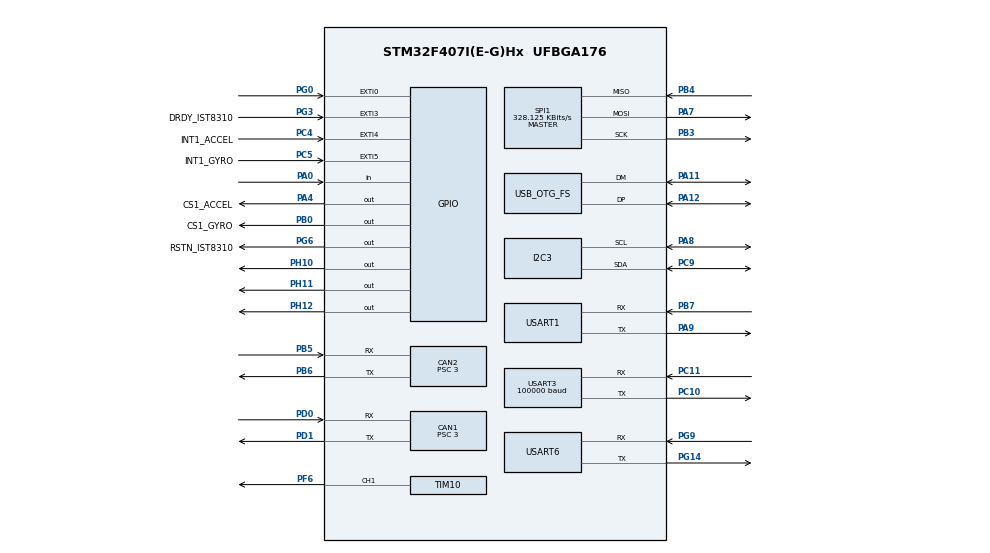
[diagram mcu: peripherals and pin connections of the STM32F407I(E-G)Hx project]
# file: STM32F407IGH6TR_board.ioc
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CAN1.ABOM=ENABLE
CAN1.BS1=CAN_BS1_9TQ
CAN1.BS2=CAN_BS2_4TQ
CAN1.CalculateBaudRate=1000000
CAN1.CalculateTimeBit=1000
CAN1.CalculateTimeQuantum=71.42857142857143
CAN1.Prescaler=3
CAN2.ABOM=ENABLE
CAN2.BS1=CAN_BS1_9TQ
CAN2.BS2=CAN_BS2_4TQ
CAN2.CalculateBaudRate=1000000
CAN2.CalculateTimeBit=1000
CAN2.CalculateTimeQuantum=71.42857142857143
CAN2.Prescaler=3
Dma.Request0=USART6_RX
Dma.Request1=USART6_TX
Dma.Request2=USART3_RX
Dma.Request3=USART1_RX
Dma.Request4=USART1_TX
Dma.Request5=SPI1_RX
Dma.Request6=SPI1_TX
Dma.SPI1_RX.5.Direction=DMA_PERIPH_TO_MEMORY
Dma.SPI1_RX.5.FIFOMode=DMA_FIFOMODE_DISABLE
Dma.SPI1_RX.5.Instance=DMA2_Stream2
Dma.SPI1_RX.5.MemDataAlignment=DMA_MDATAALIGN_BYTE
Dma.SPI1_RX.5.MemInc=DMA_MINC_ENABLE
Dma.SPI1_RX.5.Mode=DMA_NORMAL
Dma.SPI1_RX.5.PeriphDataAlignment=DMA_PDATAALIGN_BYTE
Dma.SPI1_RX.5.PeriphInc=DMA_PINC_DISABLE
Dma.SPI1_RX.5.Priority=DMA_PRIORITY_VERY_HIGH
Dma.SPI1_TX.6.Direction=DMA_MEMORY_TO_PERIPH
Dma.SPI1_TX.6.FIFOMode=DMA_FIFOMODE_DISABLE
Dma.SPI1_TX.6.Instance=DMA2_Stream3
Dma.SPI1_TX.6.MemDataAlignment=DMA_MDATAALIGN_BYTE
Dma.SPI1_TX.6.MemInc=DMA_MINC_ENABLE
Dma.SPI1_TX.6.Mode=DMA_NORMAL
Dma.SPI1_TX.6.PeriphDataAlignment=DMA_PDATAALIGN_BYTE
Dma.SPI1_TX.6.PeriphInc=DMA_PINC_DISABLE
Dma.SPI1_TX.6.Priority=DMA_PRIORITY_HIGH
Dma.USART1_RX.3.Direction=DMA_PERIPH_TO_MEMORY
Dma.USART1_RX.3.FIFOMode=DMA_FIFOMODE_DISABLE
Dma.USART1_RX.3.Instance=DMA2_Stream5
Dma.USART1_RX.3.MemDataAlignment=DMA_MDATAALIGN_BYTE
Dma.USART1_RX.3.MemInc=DMA_MINC_ENABLE
Dma.USART1_RX.3.Mode=DMA_CIRCULAR
Dma.USART1_RX.3.PeriphDataAlignment=DMA_PDATAALIGN_BYTE
Dma.USART1_RX.3.PeriphInc=DMA_PINC_DISABLE
Dma.USART1_RX.3.Priority=DMA_PRIORITY_LOW
Dma.USART1_TX.4.Direction=DMA_MEMORY_TO_PERIPH
Dma.USART1_TX.4.FIFOMode=DMA_FIFOMODE_DISABLE
Dma.USART1_TX.4.Instance=DMA2_Stream7
Dma.USART1_TX.4.MemDataAlignment=DMA_MDATAALIGN_BYTE
Dma.USART1_TX.4.MemInc=DMA_MINC_ENABLE
Dma.USART1_TX.4.Mode=DMA_NORMAL
Dma.USART1_TX.4.PeriphDataAlignment=DMA_PDATAALIGN_BYTE
Dma.USART1_TX.4.PeriphInc=DMA_PINC_DISABLE
Dma.USART1_TX.4.Priority=DMA_PRIORITY_LOW
Dma.USART3_RX.2.Direction=DMA_PERIPH_TO_MEMORY
Dma.USART3_RX.2.FIFOMode=DMA_FIFOMODE_DISABLE
Dma.USART3_RX.2.Instance=DMA1_Stream1
Dma.USART3_RX.2.MemDataAlignment=DMA_MDATAALIGN_BYTE
Dma.USART3_RX.2.MemInc=DMA_MINC_ENABLE
Dma.USART3_RX.2.Mode=DMA_CIRCULAR
Dma.USART3_RX.2.PeriphDataAlignment=DMA_PDATAALIGN_BYTE
Dma.USART3_RX.2.PeriphInc=DMA_PINC_DISABLE
Dma.USART3_RX.2.Priority=DMA_PRIORITY_VERY_HIGH
Dma.USART6_RX.0.Direction=DMA_PERIPH_TO_MEMORY
Dma.USART6_RX.0.FIFOMode=DMA_FIFOMODE_DISABLE
Dma.USART6_RX.0.Instance=DMA2_Stream1
Dma.USART6_RX.0.MemDataAlignment=DMA_MDATAALIGN_BYTE
Dma.USART6_RX.0.MemInc=DMA_MINC_ENABLE
Dma.USART6_RX.0.Mode=DMA_CIRCULAR
Dma.USART6_RX.0.PeriphDataAlignment=DMA_PDATAALIGN_BYTE
Dma.USART6_RX.0.PeriphInc=DMA_PINC_DISABLE
Dma.USART6_RX.0.Priority=DMA_PRIORITY_LOW
Dma.USART6_TX.1.Direction=DMA_MEMORY_TO_PERIPH
Dma.USART6_TX.1.FIFOMode=DMA_FIFOMODE_DISABLE
Dma.USART6_TX.1.Instance=DMA2_Stream6
Dma.USART6_TX.1.MemDataAlignment=DMA_MDATAALIGN_BYTE
Dma.USART6_TX.1.MemInc=DMA_MINC_ENABLE
Dma.USART6_TX.1.Mode=DMA_NORMAL
Dma.USART6_TX.1.PeriphDataAlignment=DMA_PDATAALIGN_BYTE
Dma.USART6_TX.1.PeriphInc=DMA_PINC_DISABLE
Dma.USART6_TX.1.Priority=DMA_PRIORITY_LOW
FREERTOS.INCLUDE_vTaskDelayUntil=1
FREERTOS.INCLUDE_xTaskGetHandle=1
FREERTOS.Tasks01=defaultTask,0,128,StartDefaultTask,Default,NULL,Dynamic,NULL,NULL;GimbalControlTa,2,2048,GimbalControlTask,As weak,NULL,Dynamic,NULL,NULL;VisionComTa,-2,1024,VisionComTask,As weak,NULL,Dynamic,NULL,NULL;imuTask,3,1024,INS_task,As weak,NULL,Static,imuTaskBuffer,imuTaskControlBlock
I2C3.I2C_Mode=I2C_Fast
Mcu.Family=STM32F4
Mcu.Name=STM32F407I(E-G)Hx
Mcu.Package=UFBGA176
NVIC.CAN1_RX0_IRQn=true\:5\:0\:false\:false\:true\:true\:true\:true\:true
NVIC.CAN2_RX0_IRQn=true\:5\:0\:false\:false\:true\:true\:true\:true\:true
NVIC.DMA1_Stream1_IRQn=true\:5\:0\:false\:false\:true\:true\:false\:true\:true
NVIC.DMA2_Stream1_IRQn=true\:5\:0\:false\:false\:true\:true\:false\:true\:true
NVIC.DMA2_Stream2_IRQn=true\:5\:0\:false\:false\:true\:true\:false\:true\:true
NVIC.DMA2_Stream3_IRQn=true\:5\:0\:false\:false\:true\:true\:false\:true\:true
NVIC.DMA2_Stream5_IRQn=true\:5\:0\:false\:false\:true\:false\:false\:true\:true
NVIC.DMA2_Stream6_IRQn=true\:5\:0\:false\:false\:true\:true\:false\:true\:true
NVIC.DMA2_Stream7_IRQn=true\:5\:0\:false\:false\:true\:true\:false\:true\:true
NVIC.EXTI0_IRQn=true\:6\:0\:true\:false\:true\:true\:true\:true\:true
NVIC.EXTI3_IRQn=true\:5\:0\:false\:false\:true\:true\:true\:true\:true
NVIC.EXTI4_IRQn=true\:5\:0\:false\:false\:true\:true\:true\:true\:true
NVIC.EXTI9_5_IRQn=true\:5\:0\:false\:false\:true\:true\:true\:true\:true
NVIC.OTG_FS_IRQn=true\:5\:0\:false\:false\:true\:true\:true\:true\:true
NVIC.PriorityGroup=NVIC_PRIORITYGROUP_4
NVIC.TIM5_IRQn=true\:5\:0\:true\:false\:true\:true\:true\:true\:true
NVIC.USART1_IRQn=true\:5\:0\:false\:false\:true\:true\:true\:true\:true
NVIC.USART3_IRQn=true\:5\:0\:false\:false\:true\:true\:true\:true\:true
NVIC.USART6_IRQn=true\:5\:0\:false\:false\:true\:true\:true\:true\:true
PA0-WKUP.GPIO_PuPd=GPIO_PULLUP
PA0-WKUP.Signal=GPIO_Input
PA11.Mode=Device_Only
PA11.Signal=USB_OTG_FS_DM
PA12.Mode=Device_Only
PA12.Signal=USB_OTG_FS_DP
PA13.Mode=Serial_Wire
PA13.Signal=SYS_JTMS-SWDIO
PA14.Mode=Serial_Wire
PA14.Signal=SYS_JTCK-SWCLK
PA4.GPIO_Label=CS1_ACCEL
PA4.GPIO_PuPd=GPIO_PULLUP
PA4.GPIO_Speed=GPIO_SPEED_FREQ_HIGH
PA4.PinState=GPIO_PIN_SET
PA4.Signal=GPIO_Output
PA7.GPIO_PuPd=GPIO_PULLUP
PA7.Mode=Full_Duplex_Master
PA7.Signal=SPI1_MOSI
PA8.GPIO_Pu=GPIO_PULLUP
PA8.Mode=I2C
PA8.Signal=I2C3_SCL
PA9.Mode=Asynchronous
PA9.Signal=USART1_TX
PB0.GPIO_Label=CS1_GYRO
PB0.GPIO_PuPd=GPIO_PULLUP
PB0.GPIO_Speed=GPIO_SPEED_FREQ_HIGH
PB0.PinState=GPIO_PIN_SET
PB0.Signal=GPIO_Output
PB3.GPIO_PuPd=GPIO_PULLUP
PB3.Mode=Full_Duplex_Master
PB3.Signal=SPI1_SCK
PB4.GPIO_PuPd=GPIO_PULLUP
PB4.Mode=Full_Duplex_Master
PB4.Signal=SPI1_MISO
PB5.Mode=CAN_Activate
PB5.Signal=CAN2_RX
PB6.Mode=CAN_Activate
PB6.Signal=CAN2_TX
PB7.Mode=Asynchronous
PB7.Signal=USART1_RX
PC10.Mode=Asynchronous
PC10.Signal=USART3_TX
PC11.Mode=Asynchronous
PC11.Signal=USART3_RX
PC4.GPIO_Label=INT1_ACCEL
PC4.GPIO_ModeDefaultEXTI=GPIO_MODE_IT_FALLING
PC4.GPIO_PuPd=GPIO_PULLUP
PC4.Signal=GPXTI4
PC5.GPIO_Label=INT1_GYRO
PC5.GPIO_ModeDefaultEXTI=GPIO_MODE_IT_FALLING
PC5.GPIO_PuPd=GPIO_PULLUP
PC5.Signal=GPXTI5
PC9.GPIO_Pu=GPIO_PULLUP
PC9.Mode=I2C
PC9.Signal=I2C3_SDA
PD0.Mode=CAN_Activate
PD0.Signal=CAN1_RX
PD1.Mode=CAN_Activate
PD1.Signal=CAN1_TX
PF6.GPIO_PuPd=GPIO_PULLUP
PF6.GPIO_Speed=GPIO_SPEED_FREQ_HIGH
PF6.Signal=S_TIM10_CH1
PG0.GPIO_ModeDefaultEXTI=GPIO_MODE_IT_FALLING
PG0.GPIO_PuPd=GPIO_PULLUP
PG0.Signal=GPXTI0
PG14.Mode=Asynchronous
PG14.Signal=USART6_TX
PG3.GPIO_Label=DRDY_IST8310
PG3.GPIO_ModeDefaultEXTI=GPIO_MODE_IT_FALLING
PG3.GPIO_PuPd=GPIO_PULLUP
PG3.Signal=GPXTI3
PG6.GPIO_Label=RSTN_IST8310
PG6.GPIO_PuPd=GPIO_PULLUP
PG6.GPIO_Speed=GPIO_SPEED_FREQ_MEDIUM
PG6.PinState=GPIO_PIN_SET
PG6.Signal=GPIO_Output
PG9.Mode=Asynchronous
PG9.Signal=USART6_RX
PH0-OSC_IN.Mode=HSE-External-Oscillator
PH0-OSC_IN.Signal=RCC_OSC_IN
PH1-OSC_OUT.Mode=HSE-External-Oscillator
PH1-OSC_OUT.Signal=RCC_OSC_OUT
PH10.PinState=GPIO_PIN_RESET
PH10.Signal=GPIO_Output
PH11.PinState=GPIO_PIN_RESET
PH11.Signal=GPIO_Output
PH12.PinState=GPIO_PIN_RESET
PH12.Signal=GPIO_Output
ProjectManager.HeapSize=0x1000
ProjectManager.StackSize=0x1000
ProjectManager.TargetToolchain=STM32CubeIDE
RCC.48MHZClocksFreq_Value=48000000
RCC.AHBFreq_Value=168000000
RCC.APB1CLKDivider=RCC_HCLK_DIV4
RCC.APB1Freq_Value=42000000
RCC.APB1TimFreq_Value=84000000
RCC.APB2CLKDivider=RCC_HCLK_DIV2
RCC.APB2Freq_Value=84000000
RCC.APB2TimFreq_Value=168000000
RCC.CortexFreq_Value=168000000
RCC.HCLKFreq_Value=168000000
RCC.HSE_VALUE=12000000
RCC.HSI_VALUE=16000000
RCC.LSE_VALUE=32768
RCC.PLLM=6
RCC.PLLN=168
RCC.PLLQ=7
RCC.SYSCLKFreq_VALUE=168000000
RCC.SYSCLKSource=RCC_SYSCLKSOURCE_PLLCLK
RCC.VCOOutputFreq_Value=336000000
SH.S_TIM10_CH1.0=TIM10_CH1,PWM Generation1 CH1
SPI1.BaudRatePrescaler=SPI_BAUDRATEPRESCALER_256
SPI1.CLKPhase=SPI_PHASE_2EDGE
SPI1.CLKPolarity=SPI_POLARITY_HIGH
SPI1.CalculateBaudRate=328.125 KBits/s
SPI1.Direction=SPI_DIRECTION_2LINES
SPI1.Mode=SPI_MODE_MASTER
SPI1.VirtualType=VM_MASTER
STMicroelectronics.X-CUBE-ALGOBUILD.1.3.0.LibraryCcDSPOoLibraryJjDSPOoLibrary=true
TIM10.Channel=TIM_CHANNEL_1
TIM10.Period=4999
TIM5.AutoReloadPreload=TIM_AUTORELOAD_PRELOAD_ENABLE
TIM5.Period=50
TIM5.Prescaler=8399
USART1.VirtualMode=VM_ASYNC
USART3.BaudRate=100000
USART3.VirtualMode=VM_ASYNC
USART6.VirtualMode=VM_ASYNC
USB_DEVICE.CLASS_NAME_FS=CDC
USB_DEVICE.VirtualMode-CDC_FS=Cdc
USB_DEVICE.VirtualModeFS=Cdc_FS
USB_OTG_FS.VirtualMode=Device_Only
VP_FREERTOS_VS_CMSIS_V1.Mode=CMSIS_V1
VP_IWDG_VS_IWDG.Mode=IWDG_Activate
VP_STMicroelectronics.X-CUBE-ALGOBUILD_VS_DSPOoLibraryJjLibrary_1.3.0_1.3.0.Mode=DSPOoLibraryJjLibrary
VP_TIM10_VS_ClockSourceINT.Mode=Enable_Timer
VP_TIM5_VS_ClockSourceINT.Mode=Internal
VP_USB_DEVICE_VS_USB_DEVICE_CDC_FS.Mode=CDC_FS
board=custom

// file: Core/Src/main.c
/* USER CODE BEGIN Header */
/**
  ******************************************************************************
  * @file           : main.c
  * @brief          : Main program body
  ******************************************************************************
  * @attention
  *
  * Copyright (c) 2022 STMicroelectronics.
  * All rights reserved.
  *
  * This software is licensed under terms that can be found in the LICENSE file
  * in the root directory of this software component.
  * If no LICENSE file comes with this software, it is provided AS-IS.
  *
  ******************************************************************************
  */
/* USER CODE END Header */
#include "main.h"
#include "cmsis_os.h"
#include "can.h"
#include "dma.h"
#include "i2c.h"
#include "iwdg.h"
#include "spi.h"
#include "tim.h"
#include "usart.h"
#include "usb_device.h"
#include "gpio.h"

/* USER CODE BEGIN PM */
void BSP_Init(void)
{
	HAL_Init();
	SystemClock_Config();
	MX_GPIO_Init();
	MX_DMA_Init();
	MX_USART6_UART_Init();//δʹ��
	MX_USART3_UART_Init();//ң����
	MX_CAN1_Init();
	MX_CAN2_Init();
	MX_USART1_UART_Init();//��ӡ

	MX_I2C3_Init();
	MX_SPI1_Init();

	MX_TIM10_Init();
	MX_TIM5_Init();
//	MX_IWDG_Init();
//	MX_FREERTOS_Init();
}
/* USER CODE END PM */

void SystemClock_Config(void);
void MX_FREERTOS_Init(void);

void SystemClock_Config(void)
{
  RCC_OscInitTypeDef RCC_OscInitStruct = {0};
  RCC_ClkInitTypeDef RCC_ClkInitStruct = {0};

  /** Configure the main internal regulator output voltage
  */
  __HAL_RCC_PWR_CLK_ENABLE();
  __HAL_PWR_VOLTAGESCALING_CONFIG(PWR_REGULATOR_VOLTAGE_SCALE1);

	// 先将时钟源选择为内部时钟
	RCC_ClkInitStruct.ClockType = RCC_CLOCKTYPE_SYSCLK;
	RCC_ClkInitStruct.SYSCLKSource = RCC_SYSCLKSOURCE_HSI;
	if (HAL_RCC_ClockConfig(&RCC_ClkInitStruct, FLASH_LATENCY_5) != HAL_OK)
	{
		Error_Handler();
	}
  /** Initializes the RCC Oscillators according to the specified parameters
  * in the RCC_OscInitTypeDef structure.
  */
  RCC_OscInitStruct.OscillatorType = RCC_OSCILLATORTYPE_LSI|RCC_OSCILLATORTYPE_HSE;
  RCC_OscInitStruct.HSEState = RCC_HSE_ON;
  RCC_OscInitStruct.LSIState = RCC_LSI_ON;
  RCC_OscInitStruct.PLL.PLLState = RCC_PLL_ON;
  RCC_OscInitStruct.PLL.PLLSource = RCC_PLLSOURCE_HSE;
  RCC_OscInitStruct.PLL.PLLM = 6;
  RCC_OscInitStruct.PLL.PLLN = 168;
  RCC_OscInitStruct.PLL.PLLP = RCC_PLLP_DIV2;
  RCC_OscInitStruct.PLL.PLLQ = 7;
  if (HAL_RCC_OscConfig(&RCC_OscInitStruct) != HAL_OK)
  {
    Error_Handler();
  }

  /** Initializes the CPU, AHB and APB buses clocks
  */
  RCC_ClkInitStruct.ClockType = RCC_CLOCKTYPE_HCLK|RCC_CLOCKTYPE_SYSCLK
                              |RCC_CLOCKTYPE_PCLK1|RCC_CLOCKTYPE_PCLK2;
  RCC_ClkInitStruct.SYSCLKSource = RCC_SYSCLKSOURCE_PLLCLK;
  RCC_ClkInitStruct.AHBCLKDivider = RCC_SYSCLK_DIV1;
  RCC_ClkInitStruct.APB1CLKDivider = RCC_HCLK_DIV4;
  RCC_ClkInitStruct.APB2CLKDivider = RCC_HCLK_DIV2;

  if (HAL_RCC_ClockConfig(&RCC_ClkInitStruct, FLASH_LATENCY_5) != HAL_OK)
  {
    Error_Handler();
  }
}

void Error_Handler(void)
{
	__disable_irq();
	while (1)
	{
	}
}
